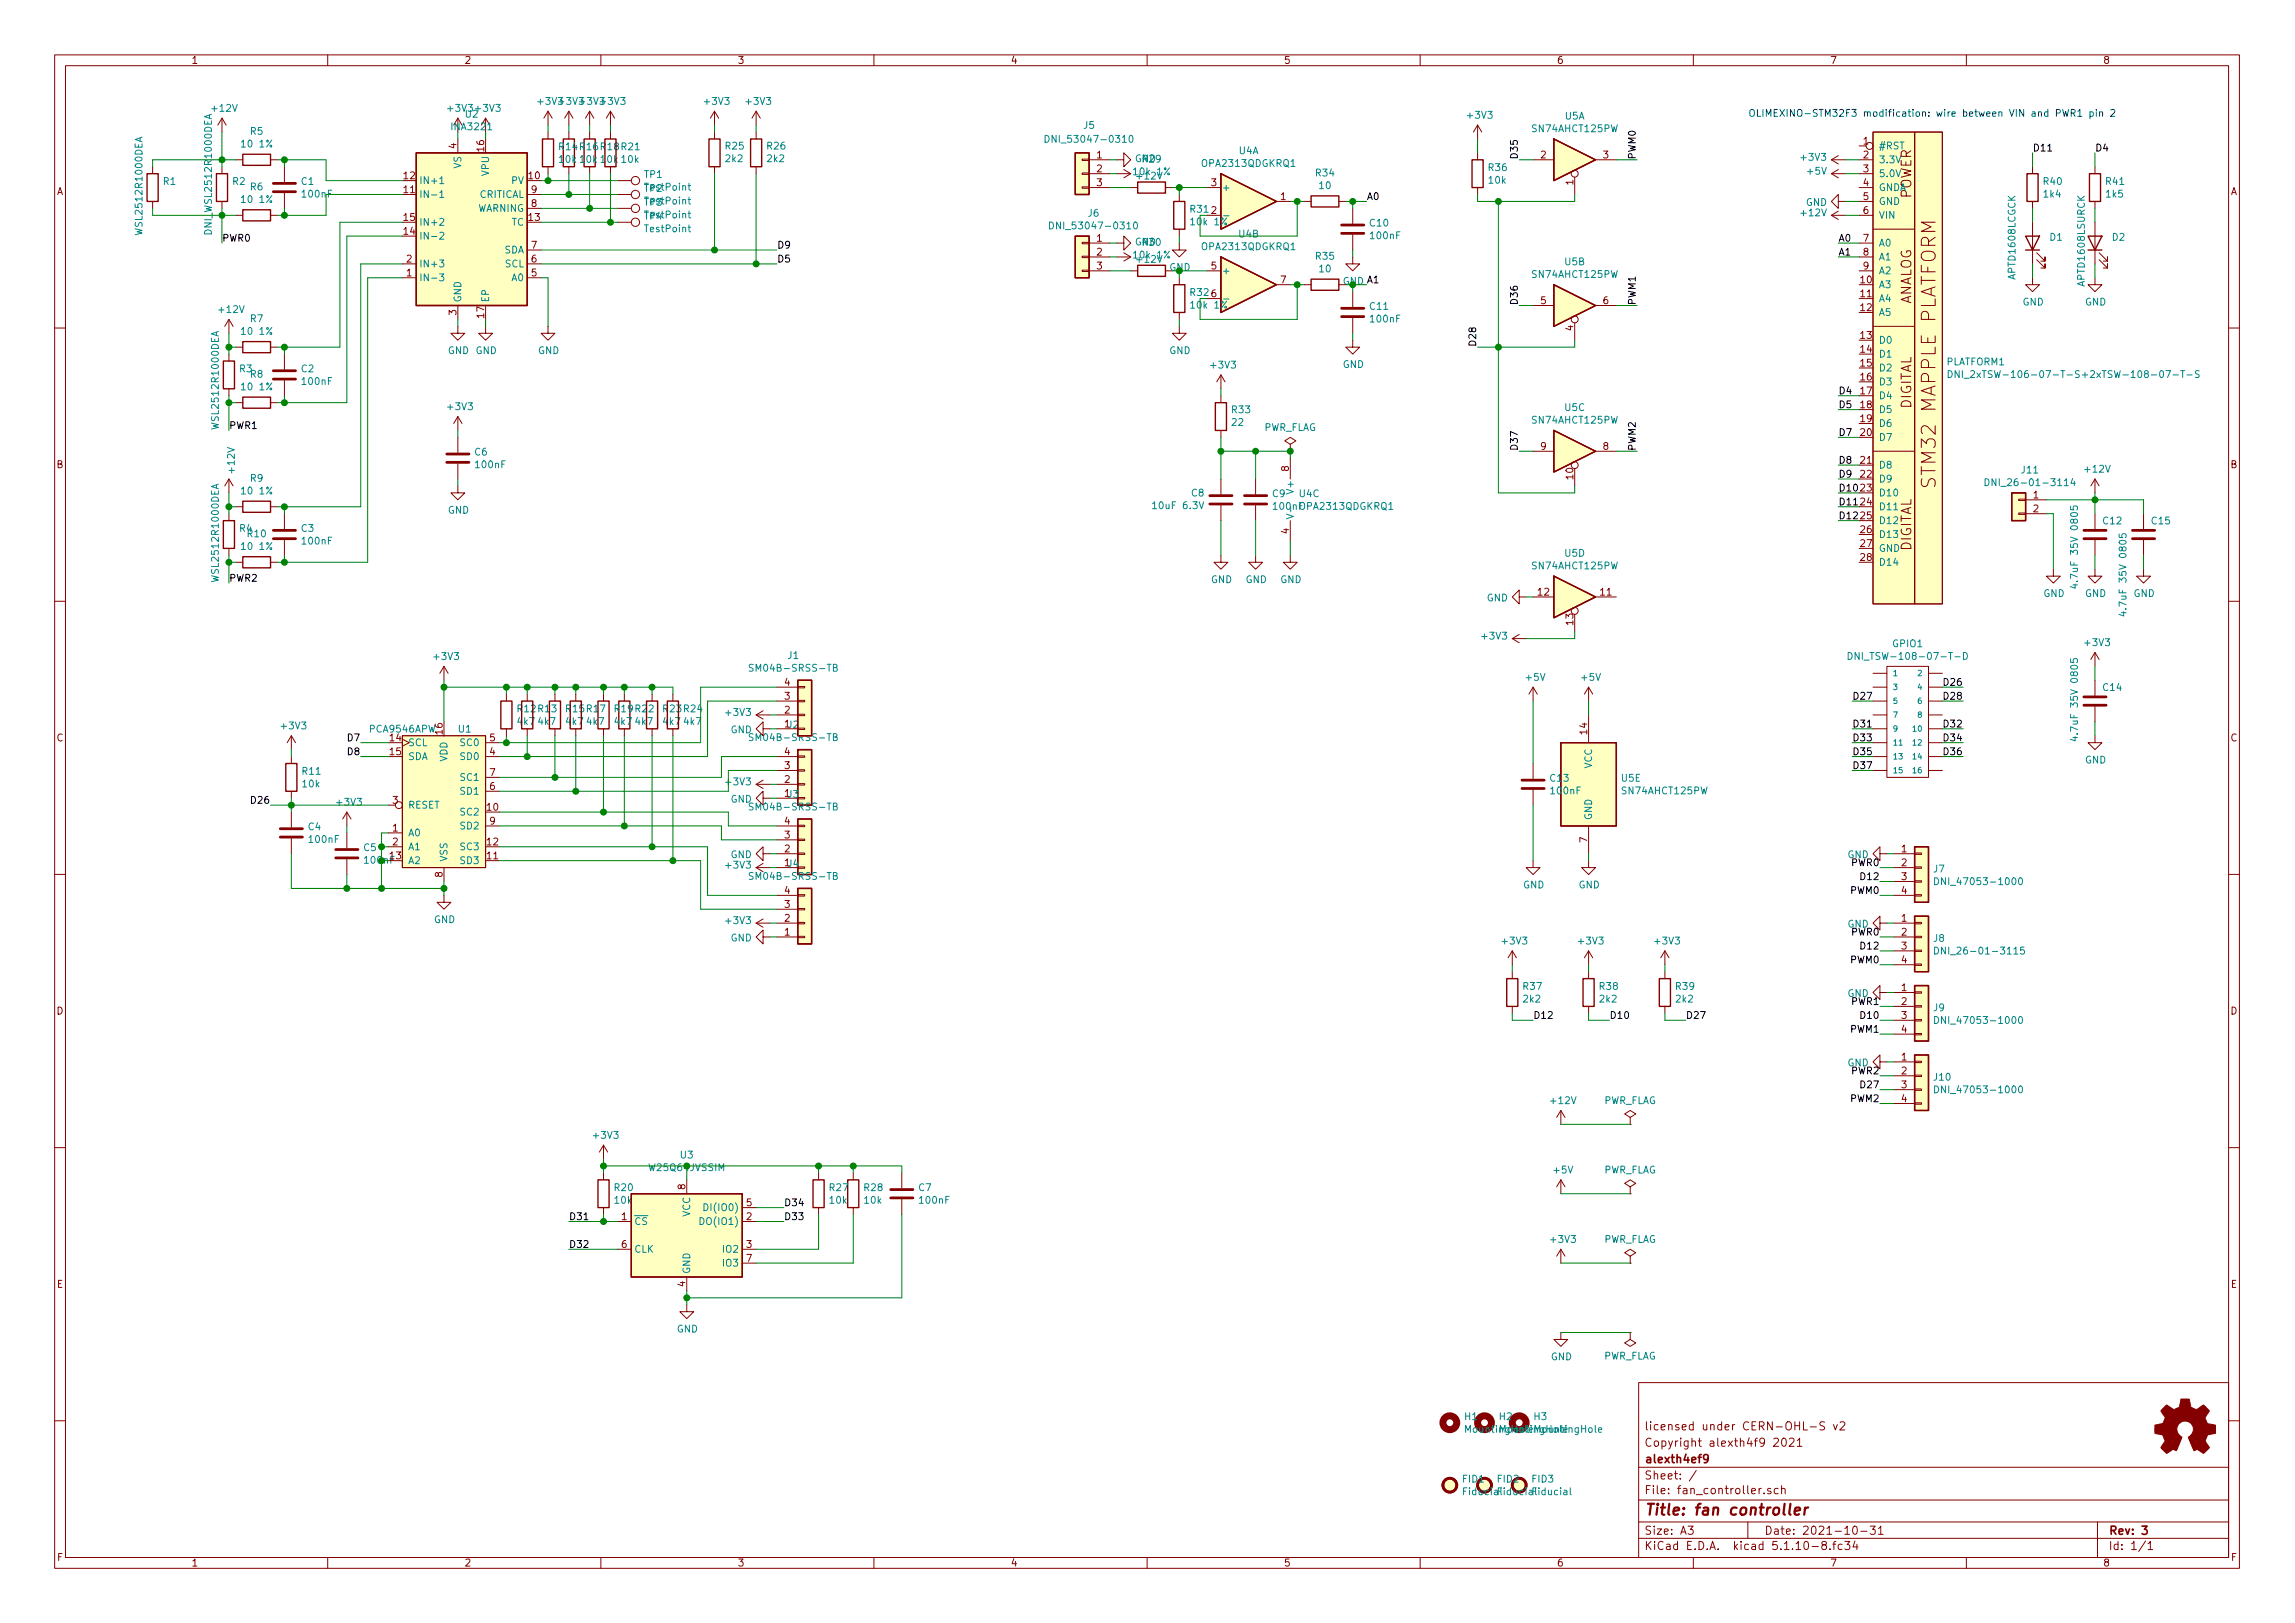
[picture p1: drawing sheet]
<svg xmlns="http://www.w3.org/2000/svg" width="420mm" height="297mm" viewBox="0 0 420 297" stroke-linecap="round" stroke-linejoin="round" font-family="sans-serif">
<defs><g id="words">
<text font-size="3.5" fill="#840000" x="354.4" y="88.7" transform="rotate(-90 354.4 88.7)">STM32 MAPPLE PLATFORM</text>
<text font-size="2.8" fill="#840000" x="301" y="277.3">Title: fan controller</text>
<g font-size="2.5" fill="#840000">
<text x="349.9" y="36.5" transform="rotate(-90 349.9 36.5)">POWER</text>
<text x="349.9" y="55.9" transform="rotate(-90 349.9 55.9)">ANALOG</text>
<text x="349.9" y="75" transform="rotate(-90 349.9 75)">DIGITAL</text>
<text x="349.9" y="101" transform="rotate(-90 349.9 101)">DIGITAL</text>
</g>
<g font-size="2.1" fill="#840000">
<text x="301" y="261.8">licensed under CERN-OHL-S v2</text>
<text x="301" y="267.8">alexth4ef9</text>
<text x="301" y="264.8">Copyright alexth4f9 2021</text>
<text x="301" y="273.5">File: fan_controller.sch</text>
<text x="301" y="270.8">Sheet: /</text>
<text x="301" y="280.9">Size: A3</text>
<text x="323" y="280.9">Date: 2021-10-31</text>
<text x="386" y="280.9">Rev: 3</text>
<text x="301" y="283.7">KiCad E.D.A. kicad 5.1.10-8.fc34</text>
<text x="386" y="283.7">Id: 1/1</text>
</g>
<g font-size="1.8" fill="#840000">
<text x="35" y="11.7">1</text>
<text x="85" y="11.7">2</text>
<text x="135" y="11.7">3</text>
<text x="185" y="11.7">4</text>
<text x="235" y="11.7">5</text>
<text x="285" y="11.7">6</text>
<text x="335" y="11.7">7</text>
<text x="385" y="11.7">8</text>
<text x="83.6" y="27.2" transform="rotate(-90 83.6 27.2)">4</text>
<text x="88.6" y="27.7" transform="rotate(-90 88.6 27.7)">16</text>
<text x="200.8" y="29">1</text>
<text x="282.1" y="29">2</text>
<text x="293.5" y="29">3</text>
<text x="341.1" y="26.5">1</text>
<text x="341.1" y="29">2</text>
<text x="10.4" y="35.7">A</text>
<text x="74" y="35.3">11</text>
<text x="74" y="32.8">12</text>
<text x="96.8" y="32.8">10</text>
<text x="97.3" y="35.3">9</text>
<text x="200.8" y="31.5">2</text>
<text x="200.8" y="34.1">3</text>
<text x="221.8" y="34.1">3</text>
<text x="288" y="33.8" transform="rotate(-90 288 33.8)">1</text>
<text x="341.1" y="31.5">3</text>
<text x="341.1" y="34.1">4</text>
<text x="408.4" y="35.7">A</text>
<text x="74" y="40.4">15</text>
<text x="96.8" y="40.4">13</text>
<text x="97.3" y="37.9">8</text>
<text x="221.8" y="39.2">2</text>
<text x="234.5" y="36.6">1</text>
<text x="341.1" y="36.6">5</text>
<text x="341.1" y="39.2">6</text>
<text x="74" y="43">14</text>
<text x="97.3" y="45.5">7</text>
<text x="200.8" y="44.2">1</text>
<text x="200.8" y="46.8">2</text>
<text x="341.1" y="44.2">7</text>
<text x="341.1" y="46.8">8</text>
<text x="74.4" y="50.6">1</text>
<text x="74.4" y="48">2</text>
<text x="97.3" y="50.6">5</text>
<text x="97.3" y="48">6</text>
<text x="200.8" y="49.3">3</text>
<text x="221.8" y="49.3">5</text>
<text x="234.5" y="51.9">7</text>
<text x="340.7" y="51.9">10</text>
<text x="341.1" y="49.3">9</text>
<text x="83.6" y="57.7" transform="rotate(-90 83.6 57.7)">3</text>
<text x="88.6" y="58.2" transform="rotate(-90 88.6 58.2)">17</text>
<text x="221.8" y="54.4">6</text>
<text x="282.1" y="55.7">5</text>
<text x="293.5" y="55.7">6</text>
<text x="340.7" y="54.4">11</text>
<text x="340.7" y="56.9">12</text>
<text x="288" y="60.5" transform="rotate(-90 288 60.5)">4</text>
<text x="340.7" y="62">13</text>
<text x="340.7" y="64.6">14</text>
<text x="340.7" y="67.1">15</text>
<text x="340.7" y="69.6">16</text>
<text x="340.7" y="72.2">17</text>
<text x="340.7" y="74.7">18</text>
<text x="340.7" y="77.3">19</text>
<text x="282.1" y="82.3">9</text>
<text x="293.5" y="82.3">8</text>
<text x="340.7" y="79.8">20</text>
<text x="10.4" y="85.7">B</text>
<text x="236" y="86.2" transform="rotate(-90 236 86.2)">8</text>
<text x="288" y="87.7" transform="rotate(-90 288 87.7)">10</text>
<text x="340.7" y="84.9">21</text>
<text x="340.7" y="87.4">22</text>
<text x="340.7" y="90">23</text>
<text x="408.4" y="85.7">B</text>
<text x="340.7" y="92.5">24</text>
<text x="340.7" y="95">25</text>
<text x="372.3" y="91.2">1</text>
<text x="372.3" y="93.8">2</text>
<text x="236" y="97.7" transform="rotate(-90 236 97.7)">4</text>
<text x="340.7" y="97.6">26</text>
<text x="340.7" y="100.1">27</text>
<text x="340.7" y="102.7">28</text>
<text x="281.6" y="109">12</text>
<text x="293" y="109">11</text>
<text x="288" y="114.3" transform="rotate(-90 288 114.3)">13</text>
<text x="143.7" y="125.5">4</text>
<text x="143.7" y="130.6">2</text>
<text x="143.7" y="128.1">3</text>
<text x="10.4" y="135.7">C</text>
<text x="71.4" y="135.7">14</text>
<text x="81" y="134.4" transform="rotate(-90 81 134.4)">16</text>
<text x="89.7" y="135.7">5</text>
<text x="143.7" y="133.1">1J2</text>
<text x="290.6" y="134.4" transform="rotate(-90 290.6 134.4)">14</text>
<text x="408.4" y="135.7">C</text>
<text x="71.4" y="138.2">15</text>
<text x="89.7" y="138.2">4</text>
<text x="89.7" y="142">7</text>
<text x="143.7" y="143.3">2</text>
<text x="143.7" y="140.8">3</text>
<text x="143.7" y="138.2">4</text>
<text x="71.9" y="147.1">3</text>
<text x="89.2" y="148.4">10</text>
<text x="89.7" y="144.6">6</text>
<text x="71.9" y="152.2">1</text>
<text x="71.9" y="154.7">2</text>
<text x="89.2" y="154.7">12</text>
<text x="89.7" y="150.9">9</text>
<text x="143.7" y="156">2</text>
<text x="143.7" y="153.5">3</text>
<text x="143.7" y="150.9">4</text>
<text x="290.6" y="154.2" transform="rotate(-90 290.6 154.2)">7</text>
<text x="348.1" y="156">1</text>
<text x="71.4" y="157.3">13</text>
<text x="81" y="160.5" transform="rotate(-90 81 160.5)">8</text>
<text x="89.2" y="157.3">11</text>
<text x="348.1" y="158.5">2</text>
<text x="348.1" y="161.1">3</text>
<text x="143.7" y="166.2">3</text>
<text x="143.7" y="163.6">4</text>
<text x="348.1" y="163.6">4</text>
<text x="143.7" y="171.2">1</text>
<text x="143.7" y="168.7">2</text>
<text x="348.1" y="168.7">1</text>
<text x="348.1" y="171.2">2</text>
<text x="348.1" y="173.8">3</text>
<text x="348.1" y="176.3">4</text>
<text x="10.4" y="185.7">D</text>
<text x="348.1" y="181.4">1</text>
<text x="348.1" y="183.9">2</text>
<text x="408.4" y="185.7">D</text>
<text x="348.1" y="186.5">3</text>
<text x="348.1" y="189">4</text>
<text x="348.1" y="194.1">1</text>
<text x="348.1" y="196.6">2</text>
<text x="348.1" y="199.2">3</text>
<text x="348.1" y="201.7">4</text>
<text x="125.5" y="217.7" transform="rotate(-90 125.5 217.7)">8</text>
<text x="136.7" y="220.8">5</text>
<text x="113.8" y="223.3">1</text>
<text x="136.7" y="223.3">2</text>
<text x="113.8" y="228.4">6</text>
<text x="136.7" y="228.4">3</text>
<text x="136.7" y="230.9">7</text>
<text x="10.4" y="235.7">E</text>
<text x="125.5" y="235.5" transform="rotate(-90 125.5 235.5)">4</text>
<text x="408.4" y="235.7">E</text>
<text x="10.5" y="285.7">F</text>
<text x="35" y="286.7">1</text>
<text x="85" y="286.7">2</text>
<text x="135" y="286.7">3</text>
<text x="185" y="286.7">4</text>
<text x="235" y="286.7">5</text>
<text x="285" y="286.7">6</text>
<text x="335" y="286.7">7</text>
<text x="385" y="286.7">8</text>
<text x="408.5" y="285.7">F</text>
</g>
<g font-size="1.8" fill="#008484">
<text x="38.9" y="20.5">+12V</text>
<text x="82.1" y="20.5">+3V3 +3V3</text>
<text x="82.9" y="23.8">INA3221</text>
<text x="85.2" y="21.5">U2</text>
<text x="98.6" y="19.2">+3V3+3V3+3V3+3V3</text>
<text x="129.1" y="19.2">+3V3</text>
<text x="136.7" y="19.2">+3V3</text>
<text x="198.4" y="23.6">J5</text>
<text x="268.8" y="21.7">+3V3</text>
<text x="286.5" y="21.9">U5A</text>
<text x="44.5" y="27">10 1%</text>
<text x="45.9" y="24.7">R5</text>
<text x="102.4" y="27.5">R14</text>
<text x="102.4" y="29.8">10k</text>
<text x="106.2" y="27.5">R16</text>
<text x="106.2" y="29.8">10k</text>
<text x="110" y="27.5">R18</text>
<text x="110.1" y="29.8">10k</text>
<text x="113.8" y="27.5">R21</text>
<text x="113.9" y="29.8">10k</text>
<text x="132.9" y="27.4">R25</text>
<text x="132.9" y="29.7">2k2</text>
<text x="140.5" y="27.4">R26</text>
<text x="140.5" y="29.7">2k2</text>
<text x="192.6" y="26.1">DNI_53047-0310</text>
<text x="209.2" y="29.8">R29</text>
<text x="226.8" y="28.2">U4A</text>
<text x="280.7" y="24.2">SN74AHCT125PW</text>
<text x="329.9" y="29.4">+3V3</text>
<text x="343.9" y="27.3">#RST</text>
<text x="343.9" y="29.9">3.3V</text>
<text x="29.9" y="33.8">R1</text>
<text x="42.6" y="33.8">R2</text>
<text x="45.9" y="34.8">R6</text>
<text x="55.2" y="33.8">C1</text>
<text x="76.7" y="33.7">IN+1</text>
<text x="84.5" y="30.8" transform="rotate(-90 84.5 30.8)">VS</text>
<text x="89.5" y="32.1" transform="rotate(-90 89.5 32.1)">VPU</text>
<text x="93.6" y="33.7">PV</text>
<text x="118" y="32.6">TP1</text>
<text x="118" y="35.1">TP2</text>
<text x="118.2" y="34.9">TestPoint</text>
<text x="207.8" y="32.1">10k 1%</text>
<text x="208.3" y="32.9">+12V</text>
<text x="220.2" y="30.5">OPA2313QDGKRQ1</text>
<text x="223.6" y="35">+</text>
<text x="240.9" y="32.3">R34</text>
<text x="241.6" y="34.6">10</text>
<text x="272.6" y="31.3">R36</text>
<text x="272.6" y="33.6">10k</text>
<text x="331" y="32">+5V</text>
<text x="343.9" y="32.4">5.0V</text>
<text x="343.9" y="35">GNDA</text>
<text x="374.2" y="33.8">R40</text>
<text x="385.6" y="33.8">R41</text>
<text x="44.5" y="37.1">10 1%</text>
<text x="55.4" y="36.2">100nF</text>
<text x="76.7" y="36.2">IN-1</text>
<text x="76.7" y="41.3">IN+2</text>
<text x="87.4" y="38.8">WARNING</text>
<text x="87.8" y="36.2">CRITICAL</text>
<text x="93.6" y="41.3">TC</text>
<text x="118" y="40.2">TP4</text>
<text x="118" y="37.7">TP3</text>
<text x="118.2" y="40">TestPoint</text>
<text x="118.2" y="37.4">TestPoint</text>
<text x="193.4" y="42">DNI_53047-0310</text>
<text x="199.2" y="39.7">J6</text>
<text x="218.3" y="41.2">10k 1%</text>
<text x="223.6" y="40">-</text>
<text x="250.9" y="41.5">C10</text>
<text x="329.9" y="39.6">+12V</text>
<text x="330.6" y="37.7">GND</text>
<text x="343.9" y="37.5">GND</text>
<text x="343.9" y="40">VIN</text>
<text x="374.2" y="36.2">1k4</text>
<text x="385.6" y="36.2">1k5</text>
<text x="26.1" y="42.5" transform="rotate(-90 26.1 42.5)">WSL2512R1000DEA</text>
<text x="38.8" y="42.4" transform="rotate(-90 38.8 42.4)">DNI_WSL2512R1000DEA</text>
<text x="76.7" y="43.9">IN-2</text>
<text x="92.3" y="46.4">SDA</text>
<text x="118.2" y="42.5">TestPoint</text>
<text x="207.8" y="47.3">10k 1%</text>
<text x="209.2" y="45">R30</text>
<text x="220.2" y="45.8">OPA2313QDGKRQ1</text>
<text x="226.8" y="43.5">U4B</text>
<text x="240.9" y="47.5">R35</text>
<text x="251" y="43.8">100nF</text>
<text x="343.9" y="45.1">A0</text>
<text x="343.9" y="47.7">A1</text>
<text x="375.3" y="44.1">D1</text>
<text x="386.7" y="44.1">D2</text>
<text x="76.7" y="51.5">IN-3</text>
<text x="76.7" y="48.9">IN+3</text>
<text x="92.5" y="48.9">SCL</text>
<text x="93.8" y="51.5">A0</text>
<text x="208.3" y="48.1">+12V</text>
<text x="223.6" y="50.2">+</text>
<text x="241.6" y="49.8">10</text>
<text x="280.7" y="50.9">SN74AHCT125PW</text>
<text x="286.5" y="48.6">U5B</text>
<text x="343.9" y="52.7">A3</text>
<text x="343.9" y="50.2">A2</text>
<text x="369" y="51" transform="rotate(-90 369 51)">APTD1608LCGCK</text>
<text x="381.7" y="52.1" transform="rotate(-90 381.7 52.1)">APTD1608LSURCK</text>
<text x="40.2" y="57.3">+12V</text>
<text x="45.9" y="59">R7</text>
<text x="84.5" y="55.4" transform="rotate(-90 84.5 55.4)">GND</text>
<text x="89.5" y="55.4" transform="rotate(-90 89.5 55.4)">EP</text>
<text x="218.3" y="56.5">10k 1%</text>
<text x="223.6" y="55.3">-</text>
<text x="250.9" y="56.7">C11</text>
<text x="251" y="59">100nF</text>
<text x="343.9" y="55.3">A4</text>
<text x="343.9" y="57.8">A5</text>
<text x="370.3" y="55.9">GND</text>
<text x="381.7" y="55.9">GND</text>
<text x="44.5" y="61.3">10 1%</text>
<text x="82" y="64.8">GND GND</text>
<text x="98.5" y="64.8">GND</text>
<text x="214.1" y="64.8">GND</text>
<text x="343.9" y="62.9">D0</text>
<text x="343.9" y="65.4">D1</text>
<text x="43.9" y="68.1">R3</text>
<text x="44.5" y="71.4">10 1%</text>
<text x="45.9" y="69.1">R8</text>
<text x="55.2" y="68.1">C2</text>
<text x="55.4" y="70.4">100nF</text>
<text x="221.8" y="67.4">+3V3</text>
<text x="245.8" y="67.3">GND</text>
<text x="343.9" y="68">D2</text>
<text x="343.9" y="70.5">D3</text>
<text x="356.3" y="66.9">PLATFORM1</text>
<text x="361.7" y="69.2">DNI_2xTSW-106-07-T-S+2xTSW-108-07-T-S</text>
<text x="82.1" y="75.1">+3V3</text>
<text x="225.6" y="75.6">R33</text>
<text x="225.6" y="77.9">22</text>
<text x="280.7" y="77.5">SN74AHCT125PW</text>
<text x="286.5" y="75.2">U5C</text>
<text x="343.9" y="73.1">D4</text>
<text x="343.9" y="75.6">D5</text>
<text x="40.1" y="78" transform="rotate(-90 40.1 78)">WSL2512R1000DEA</text>
<text x="86.9" y="83.4">C6</text>
<text x="231.3" y="78.9">PWR_FLAG</text>
<text x="343.9" y="78.1">D6</text>
<text x="343.9" y="80.7">D7</text>
<text x="43" y="86.4" transform="rotate(-90 43 86.4)">+12V</text>
<text x="45.9" y="88.2">R9</text>
<text x="87.2" y="85.7">100nF</text>
<text x="343.9" y="85.8">D8</text>
<text x="343.9" y="88.3">D9</text>
<text x="365.1" y="89">DNI_26-01-3114</text>
<text x="370.2" y="86.7">J11</text>
<text x="381.8" y="86.5">+12V</text>
<text x="44.5" y="90.5">10 1%</text>
<text x="82" y="94">GND</text>
<text x="211.5" y="93.2">10uF 6.3V</text>
<text x="218.2" y="90.9">C8</text>
<text x="233" y="91">C9</text>
<text x="233.2" y="93.3">100nFOPA2313QDGKRQ1</text>
<text x="236.9" y="90" transform="rotate(-90 236.9 90)">V+</text>
<text x="237.9" y="91">U4C</text>
<text x="343.9" y="90.8">D10</text>
<text x="343.9" y="93.4">D11</text>
<text x="343.9" y="95.9">D12</text>
<text x="385.1" y="96">C12</text>
<text x="394" y="96">C15</text>
<text x="43.9" y="97.3">R4</text>
<text x="44.5" y="100.6">10 1%</text>
<text x="45.4" y="98.3">R10</text>
<text x="55.2" y="97.3">C3</text>
<text x="55.4" y="99.7">100nF</text>
<text x="286.5" y="101.9">U5D</text>
<text x="343.9" y="98.5">D13</text>
<text x="343.9" y="101">GND</text>
<text x="40.1" y="106" transform="rotate(-90 40.1 106)">WSL2512R1000DEA</text>
<text x="221.7" y="106.7">GND</text>
<text x="228" y="106.7">GND</text>
<text x="234.4" y="106.7">GND</text>
<text x="280.7" y="104.2">SN74AHCT125PW</text>
<text x="343.9" y="103.5">D14</text>
<text x="380.4" y="106.5" transform="rotate(-90 380.4 106.5)">4.7uF 35V 0805</text>
<text x="272.2" y="110.1">GND</text>
<text x="374.1" y="109.3">GND</text>
<text x="381.7" y="109.3">GND</text>
<text x="389.3" y="111.5" transform="rotate(-90 389.3 111.5)">4.7uF 35V 0805</text>
<text x="390.6" y="109.3">GND</text>
<text x="271.4" y="117.1">+3V3</text>
<text x="346.6" y="118.5">GPIO1</text>
<text x="381.8" y="118.2">+3V3</text>
<text x="79.6" y="120.8">+3V3</text>
<text x="138.1" y="122.9">SM04B-SRSS-TB</text>
<text x="144.3" y="120.6">J1</text>
<text x="279.5" y="124.6">+5V</text>
<text x="289.6" y="124.6">+5V</text>
<text x="340.5" y="120.8">DNI_TSW-108-07-T-D</text>
<text x="94.8" y="130.4">R12</text>
<text x="98.6" y="130.4">R13</text>
<text x="103.7" y="130.4">R15</text>
<text x="107.5" y="130.4">R17</text>
<text x="112.5" y="130.4">R19</text>
<text x="116.4" y="130.4">R22</text>
<text x="121.4" y="130.4">R23</text>
<text x="125.2" y="130.4">R24</text>
<text x="133" y="131">+3V3</text>
<text x="385.1" y="126.5">C14</text>
<text x="51.6" y="133.5">+3V3</text>
<text x="67.8" y="134.1">PCA9546APW</text>
<text x="74.7" y="136.6">SCL</text>
<text x="84" y="134.1">U1</text>
<text x="84.5" y="136.6">SC0</text>
<text x="94.8" y="132.7">4k7</text>
<text x="98.6" y="132.7">4k7</text>
<text x="103.7" y="132.7">4k7</text>
<text x="107.5" y="132.7">4k7</text>
<text x="112.6" y="132.7">4k7</text>
<text x="116.4" y="132.7">4k7</text>
<text x="121.5" y="132.7">4k7</text>
<text x="125.3" y="132.7">4k7</text>
<text x="133.8" y="134.2">GND</text>
<text x="138.1" y="135.6">SM04B-SRSS-TB</text>
<text x="380.4" y="134.4" transform="rotate(-90 380.4 134.4)">4.7uF 35V 0805</text>
<text x="55.4" y="141.8">R11</text>
<text x="74.7" y="139.1">SDA</text>
<text x="81.9" y="139.4" transform="rotate(-90 81.9 139.4)">VDD</text>
<text x="84.5" y="139.1">SD0</text>
<text x="84.5" y="142.9">SC1</text>
<text x="133" y="143.7">+3V3</text>
<text x="283.9" y="143.1">C13</text>
<text x="291.5" y="140.7" transform="rotate(-90 291.5 140.7)">VCC</text>
<text x="296.9" y="143.1">U5E</text>
<text x="381.7" y="139.7">GND</text>
<text x="55.4" y="144.1">10k</text>
<text x="61.8" y="147.5">+3V3</text>
<text x="74.7" y="148">RESET</text>
<text x="84.5" y="149.3">SC2</text>
<text x="84.5" y="145.5">SD1</text>
<text x="133.8" y="146.9">GND</text>
<text x="138.1" y="148.3">SM04B-SRSS-TB</text>
<text x="143.7" y="145.8">1J3</text>
<text x="284" y="145.4">100nF</text>
<text x="297.2" y="145.4">SN74AHCT125PW</text>
<text x="56.5" y="152">C4</text>
<text x="56.7" y="154.3">100nF</text>
<text x="66.6" y="155.8">C5</text>
<text x="74.7" y="153.1">A0</text>
<text x="74.7" y="155.6">A1</text>
<text x="84.5" y="155.6">SC3</text>
<text x="84.5" y="151.8">SD2</text>
<text x="291.5" y="150.2" transform="rotate(-90 291.5 150.2)">GND</text>
<text x="74.7" y="158.2">A2</text>
<text x="81.9" y="157.8" transform="rotate(-90 81.9 157.8)">VSS</text>
<text x="84.5" y="158.2">SD3</text>
<text x="133" y="159">+3V3</text>
<text x="133.8" y="157.1">GND</text>
<text x="138.1" y="161">SM04B-SRSS-TB</text>
<text x="143.7" y="158.5">1J4</text>
<text x="338.2" y="157.1">GND</text>
<text x="354" y="159.7">J7</text>
<text x="355.5" y="162">DNI_47053-1000</text>
<text x="278.8" y="162.6">GND</text>
<text x="289" y="162.6">GND</text>
<text x="79.5" y="168.9">GND</text>
<text x="133" y="169.1">+3V3</text>
<text x="133.8" y="172.3">GND</text>
<text x="275.2" y="172.9">+3V3</text>
<text x="289.1" y="172.9">+3V3</text>
<text x="303.1" y="172.9">+3V3</text>
<text x="338.2" y="169.8">GND</text>
<text x="354" y="172.4">J8</text>
<text x="355.9" y="174.7">DNI_26-01-3115</text>
<text x="278.9" y="181.2">R37</text>
<text x="279" y="183.5">2k2</text>
<text x="292.9" y="181.2">R38</text>
<text x="292.9" y="183.5">2k2</text>
<text x="306.9" y="181.2">R39</text>
<text x="306.9" y="183.5">2k2</text>
<text x="338.2" y="182.5">GND</text>
<text x="354" y="185.1">J9</text>
<text x="355.5" y="187.4">DNI_47053-1000</text>
<text x="338.2" y="195.2">GND</text>
<text x="354.1" y="197.8">J10</text>
<text x="284" y="202.1">+12V</text>
<text x="293.5" y="202.1">PWR_FLAG</text>
<text x="355.5" y="200.1">DNI_47053-1000</text>
<text x="108.8" y="208.4">+3V3</text>
<text x="124.6" y="212">U3</text>
<text x="284.5" y="214.8">+5V</text>
<text x="293.5" y="214.8">PWR_FLAG</text>
<text x="112.5" y="218">R20</text>
<text x="112.6" y="220.3">10k</text>
<text x="129.6" y="221.7">DI(IO0)</text>
<text x="151.9" y="218">R27</text>
<text x="152" y="220.3">10k</text>
<text x="158.3" y="218">R28</text>
<text x="158.3" y="220.3">10k</text>
<text x="168.2" y="218">C7</text>
<text x="168.5" y="220.3">100nF</text>
<text x="116.1" y="224.2">CS</text>
<text x="126.4" y="222.7" transform="rotate(-90 126.4 222.7)">VCC</text>
<text x="128.7" y="224.2">DO(IO1)</text>
<text x="284" y="227.5">+3V3</text>
<text x="293.5" y="227.5">PWR_FLAG</text>
<text x="116.1" y="229.3">CLK</text>
<text x="126.4" y="233.2" transform="rotate(-90 126.4 233.2)">GND</text>
<text x="132.5" y="229.3">IO2</text>
<text x="132.5" y="231.8">IO3</text>
<text x="123.9" y="243.9">GND</text>
<text x="283.9" y="249">GND</text>
<text x="293.5" y="248.8">PWR_FLAG</text>
<text x="268.2" y="259.9">H1</text>
<text x="268.5" y="262.2">MountingHole</text>
<text x="274.5" y="259.9">H2</text>
<text x="274.9" y="262.2">MountingHole</text>
<text x="280.9" y="259.9">H3</text>
<text x="281.2" y="262.2">MountingHole</text>
<text x="267.8" y="271.3">FID1</text>
<text x="268.1" y="273.6">FiducialFiducialFiducial</text>
<text x="274.2" y="271.3">FID2</text>
<text x="280.5" y="271.3">FID3</text>
</g>
<text font-size="1.8" fill="#0000c2" x="320" y="21.4">OLIMEXINO-STM32F3 modification: wire between VIN and PWR1 pin 2</text>
<g font-size="1.8">
<text x="277.9" y="29.2" transform="rotate(-90 277.9 29.2)">D35</text>
<text x="299.5" y="29.2" transform="rotate(-90 299.5 29.2)">PWM0</text>
<text x="372.1" y="27.7">D11</text>
<text x="383.5" y="27.7">D4</text>
<text x="250.2" y="36.6">A0</text>
<text x="40.6" y="44.2">PWR0</text>
<text x="142.2" y="45.5">D9</text>
<text x="336.5" y="44.2">A0</text>
<text x="336.5" y="46.8">A1</text>
<text x="142.2" y="48">D5</text>
<text x="277.9" y="55.9" transform="rotate(-90 277.9 55.9)">D36</text>
<text x="299.5" y="55.9" transform="rotate(-90 299.5 55.9)">PWM1</text>
<text x="270.3" y="63.5" transform="rotate(-90 270.3 63.5)">D28</text>
<text x="336.5" y="74.7">D5</text>
<text x="336.5" y="72.2">D4</text>
<text x="41.9" y="78.5">PWR1</text>
<text x="277.9" y="82.6" transform="rotate(-90 277.9 82.6)">D37</text>
<text x="299.5" y="82.6" transform="rotate(-90 299.5 82.6)">PWM2</text>
<text x="336.5" y="79.8">D7</text>
<text x="336.5" y="87.4">D9</text>
<text x="336.5" y="90">D10</text>
<text x="336.5" y="84.9">D8</text>
<text x="336.5" y="95">D12</text>
<text x="336.5" y="92.5">D11</text>
<text x="41.9" y="106.5">PWR2</text>
<text x="356.2" y="125.5">D26</text>
<text x="339.1" y="128.1">D27</text>
<text x="356.2" y="128.1">D28</text>
<text x="63.8" y="135.7">D7</text>
<text x="339.1" y="135.7">D33</text>
<text x="339.1" y="133.1">D31</text>
<text x="356.2" y="135.7">D34</text>
<text x="356.2" y="133.1">D32</text>
<text x="63.8" y="138.2">D8</text>
<text x="339.1" y="138.2">D35</text>
<text x="339.1" y="140.8">D37</text>
<text x="356.2" y="138.2">D36</text>
<text x="46.3" y="147.1">D26</text>
<text x="339.1" y="158.5">PWR0</text>
<text x="340.9" y="161.1">D12</text>
<text x="338.9" y="163.6">PWM0</text>
<text x="339.1" y="171.2">PWR0</text>
<text x="340.9" y="173.8">D12</text>
<text x="338.9" y="176.3">PWM0</text>
<text x="339.1" y="183.9">PWR1</text>
<text x="280.7" y="186.5">D12</text>
<text x="294.6" y="186.5">D10</text>
<text x="308.6" y="186.5">D27</text>
<text x="338.9" y="189">PWM1</text>
<text x="340.9" y="186.5">D10</text>
<text x="339.1" y="196.6">PWR2</text>
<text x="338.9" y="201.7">PWM2</text>
<text x="340.9" y="199.2">D27</text>
<text x="143.5" y="220.8">D34</text>
<text x="104.1" y="223.3">D31</text>
<text x="143.5" y="223.3">D33</text>
<text x="104.1" y="228.4">D32</text>
</g>
<g font-size="1.8" fill="#008400">
<text x="218" y="38.9">R31</text>
<text x="214.1" y="49.6">GND</text>
<text x="245.8" y="52.1">GND A1</text>
<text x="218" y="54.2">R32</text>
<text x="66.9" y="158.1">100nF</text>
<text x="119" y="214.3">W25Q64JVSSIM</text>
</g>
<g font-size="1.4" fill="#008484">
<text x="346.5" y="123.7">1</text>
<text x="351.3" y="123.7">2</text>
<text x="346.5" y="126.3">3</text>
<text x="346.5" y="128.8">5</text>
<text x="346.5" y="131.4">7</text>
<text x="351.3" y="126.3">4</text>
<text x="351.3" y="128.8">6</text>
<text x="351.3" y="131.4">8</text>
<text x="346.5" y="136.4">11</text>
<text x="346.5" y="133.9">9</text>
<text x="350.5" y="133.9">10</text>
<text x="350.5" y="136.4">12</text>
<text x="346.5" y="139">13</text>
<text x="346.5" y="141.5">15</text>
<text x="350.5" y="139">14</text>
<text x="350.5" y="141.5">16</text>
</g>
</g></defs>
<g fill="none" stroke="#840000" stroke-width=".18">
<path d="M10 10h400v277h-400zM12 12h396v273.1h-396zM60 10v2M110 10v2M160 10v2M210 10v2M260 10v2M310 10v2M360 10v2M27.9 30.5v1.3M27.9 36.9v1.2M40.6 21.6l-.7 1.3"/>
<path d="M40.6 21.6v2.6M40.6 30.5v1.3M40.6 36.9v1.2M40.6 21.6l.8 1.3M43.2 39.4h1.2M43.2 29.2h1.2M49.5 39.4h1.3M49.5 29.2h1.3M52.1 30.5v2.8M52.1 35.3v2.8M83.8 21.6l-.7 1.3M83.8 21.6v2.6"/>
<path d="M83.8 25.4v2.6M83.8 21.6l.8 1.3M88.9 21.6l-.8 1.3M88.9 21.6v2.6M88.9 21.6l.8 1.3M96.5 38.1h2.6M96.5 35.6h2.6M100.3 20.4l-.7 1.2M100.3 20.4v2.5M100.3 24.2v1.2M100.3 30.5v1.3M100.3 20.4l.8 1.2"/>
<path d="M104.1 20.4l-.7 1.2M104.1 20.4v2.5M104.1 24.2v1.2M104.1 30.5v1.3M104.1 20.4l.8 1.2M107.9 20.4l-.7 1.2M107.9 20.4v2.5M107.9 24.2v1.2M107.9 30.5v1.3M107.9 20.4l.8 1.2M111.8 20.4l-.8 1.2M111.8 20.4v2.5"/>
<path d="M111.8 24.2v1.2M111.8 30.5v1.3M111.8 20.4l.7 1.2M113 33.1h2.6M113 38.1h2.6M113 35.6h2.6M130.8 20.4l-.8 1.2M130.8 20.4v2.5M130.8 24.2v1.2M130.8 30.5v1.3M130.8 20.4l.8 1.2M138.4 20.4l-.7 1.2"/>
<path d="M138.4 20.4v2.5M138.4 24.2v1.2M138.4 30.5v1.3M138.4 20.4l.8 1.2M198.1 34.2h1.3v.3h-1.3zM198.1 29.1h1.3v.3h-1.3zM198.1 31.7h1.3v.2h-1.3zM199.4 29.2h3.8M199.4 34.3h3.8M199.4 31.8h3.8M204.5 29.2h1.2v-1.2l1.3 1.2-1.3 1.3v-1.3M204.5 31.8h2.5"/>
<path d="M205.7 31l1.3 .8M207 34.3h1.3M207 31.8l-1.3 .7M213.4 34.3h1.2M215.9 35.6v1.3M221 34.3h2.5M233.7 36.9h2.5M238.8 36.9h1.2M245.1 36.9h1.3M247.6 38.1v2.8M270.5 22.9v2.5M270.5 28v1.2"/>
<path d="M270.5 34.3v1.3M270.5 22.9l-.8 1.3M270.5 22.9l.8 1.3M280.7 29.2h3.8M288.3 32.4v3.2M292.1 29.2h3.8M335.3 39.4h2.5M335.3 29.2h2.5M335.3 29.2l1.2 .8M335.3 39.4l1.2 .8M335.3 31.8l1.2 .7M335.3 31.8h2.5"/>
<path d="M336.5 36.9v-1.3l-1.2 1.3 1.2 1.2v-1.2h1.3M336.5 28.5l-1.2 .7M336.5 38.6l-1.2 .8M336.5 31l-1.2 .8M340.4 39.4h2.5M340.4 29.2h2.5M340.4 36.9h2.5M340.4 34.3h2.5M340.4 31.8h2.5M340.4 26.7h1.2M342.9 24.2h7.6v86.3h-7.6zM350.5 24.2h5.1v86.3h-5.1z"/>
<path d="M372.1 30.5v1.3M372.1 36.9v1.2M383.5 30.5v1.3M383.5 36.9v1.2M41.9 58.5v2.5M41.9 58.5l-.8 1.2M41.9 58.5l.8 1.2M73.7 50.8h2.5M73.7 48.3h2.5M83.8 59.7v1.3h1.3l-1.3 1.3-1.3-1.3h1.3M83.8 55.9v2.6M88.9 59.7v1.3h1.3l-1.3 1.3-1.3-1.3h1.3"/>
<path d="M96.5 50.8h2.6M96.5 48.3h2.6M96.5 45.8h2.6M100.3 59.7v1.3h1.3l-1.3 1.3-1.2-1.3h1.2M113 40.7h2.6M198.1 49.4h1.3v.3h-1.3zM198.1 44.4h1.3v.2h-1.3zM198.1 46.9h1.3v.3h-1.3zM199.4 49.6h3.8M199.4 44.5h3.8M199.4 47h3.8M204.5 44.5h1.2v-1.3l1.3 1.3-1.3 1.3v-1.3"/>
<path d="M204.5 47h2.5M205.7 46.3l1.3 .7M207 49.6h1.3M207 47l-1.3 .8M213.4 49.6h1.2M215.9 44.5v1.3h1.3l-1.3 1.2-1.3-1.2h1.3M215.9 59.7v1.3h1.3l-1.3 1.3-1.3-1.3h1.3M215.9 41.9v1.3M215.9 50.8v1.3M215.9 57.2v1.3M221 49.6h2.5M233.7 52.1h2.5"/>
<path d="M238.8 52.1h1.2M245.1 52.1h1.3M247.6 47v1.3h1.3l-1.3 1.3-1.2-1.3h1.2M247.6 43v2.8M247.6 53.4v2.8M247.6 58.2v2.8M280.7 55.9h3.8M288.3 59.1v3.2M292.1 55.9h3.8M340.4 49.6h2.5M340.4 44.5h2.5M340.4 47h2.5"/>
<path d="M342.9 41.9h7.6M342.9 59.7h7.6M354.3 40.7h-2.6l1.8 .8-1.8 .9h2.6M372.1 50.8v1.3h1.3l-1.3 1.3-1.3-1.3h1.3M372.1 40.7v7.6M372.9 47.5l1.5 1.6v-.8v.8h-.8M372.9 46.3l1.5 1.5v-.8v.8h-.8M383.5 50.8v1.3h1.3l-1.3 1.3-1.2-1.3h1.2M383.5 40.7v7.6M384.3 47.5l1.5 1.6v-.8v.8h-.7M384.3 46.3l1.5 1.5v-.8v.8h-.7M10 60h2"/>
<path d="M41.9 64.8v1.3M41.9 71.2v1.2M43.2 73.7h1.2M43.2 63.5h1.2M49.5 73.7h1.3M49.5 63.5h1.3M52.1 64.8v2.8M52.1 69.6v2.8M83.8 76.2v2.6M83.8 76.2l-.7 1.3M83.8 76.2l.8 1.3M223.5 68.6l-.7 1.3"/>
<path d="M223.5 68.6v2.6M223.5 72.4v1.3M223.5 78.8v1.2M223.5 68.6l.8 1.3M247.6 62.3v1.2h1.3l-1.3 1.3-1.2-1.3h1.2M408 60h2M41.9 87.7v2.5M41.9 94v1.3M41.9 87.7l-.8 1.2M41.9 87.7l.8 1.2M43.2 92.7h1.2M49.5 92.7h1.3"/>
<path d="M52.1 94v2.8M52.1 98.8v2.8M83.8 88.9v1.3h1.3l-1.3 1.3-1.3-1.3h1.3M83.8 80v2.8M83.8 84.9v2.8M223.5 87.7v2.8M223.5 92.5v2.8M229.9 87.7v2.8M229.9 92.5v2.8M236.2 81.3l1-.6-1-.7-1 .7 1 .6v1.3M236.2 82.6h.1M236.2 83.9v3.8"/>
<path d="M236.2 95.3v3.8M280.7 82.6h3.8M288.3 85.8v3.1M292.1 82.6h3.8M342.9 82.6h7.6M369.6 93.9h1.2v.2h-1.2zM369.6 91.3h1.2v.3h-1.2zM370.8 91.5h3.8M370.8 94h3.8M383.5 87.7v2.5M383.5 94v2.8M383.5 98.8v2.8"/>
<path d="M383.5 87.7l-.7 1.2M383.5 87.7l.8 1.2M392.4 94v2.8M392.4 98.8v2.8M10 110h2M41.9 100.4v1.2M43.2 102.9h1.2M49.5 102.9h1.3M223.5 101.6v1.3h1.3l-1.3 1.3-1.3-1.3h1.3M229.9 101.6v1.3h1.2l-1.2 1.3-1.3-1.3h1.3M236.2 101.6v1.3h1.3l-1.3 1.3-1.3-1.3h1.3M276.9 116.9l1.2 .7"/>
<path d="M276.9 116.9h2.5M278.1 109.3v-1.3l-1.2 1.3 1.2 1.2v-1.2h1.3M278.1 116.1l-1.2 .8M280.7 109.3h3.8M288.3 112.4v3.2M292.1 109.3h3.8M375.9 104.2v1.2h1.3l-1.3 1.3-1.3-1.3h1.3M383.5 104.2v1.2h1.3l-1.3 1.3-1.2-1.3h1.2M383.5 119.4v2.6M383.5 119.4l-.7 1.3M383.5 119.4l.8 1.3M392.4 104.2v1.2h1.3l-1.3 1.3-1.2-1.3h1.2"/>
<path d="M408 110h2M53.3 134.7l-.7 1.2M53.3 134.7v2.5M53.3 138.5v1.2M53.3 134.7l.8 1.2M73.7 134.7h15.2v24.1h-15.2zM73.7 135.3l1.2 .6-1.2 .7M81.3 122v2.5M81.3 122l-.8 1.2M81.3 122l.7 1.2M88.9 138.5h2.5M88.9 135.9h2.5"/>
<path d="M92.7 127v1.3M92.7 133.4v1.3M96.5 127v1.3M96.5 133.4v1.3M101.6 127v1.3M101.6 133.4v1.3M105.4 127v1.3M105.4 133.4v1.3M110.5 127v1.3M110.5 133.4v1.3M114.3 127v1.3M114.3 133.4v1.3"/>
<path d="M119.4 127v1.3M119.4 133.4v1.3M123.2 127v1.3M123.2 133.4v1.3M138.4 130.8l1.3 .8M138.4 130.8h2.6M139.7 133.4v-1.3l-1.3 1.3 1.3 1.3v-1.3h1.3M139.7 130.1l-1.3 .7M142.2 138.5h3.8M142.2 130.8h3.8M142.2 133.4h3.8M142.2 128.3h3.8"/>
<path d="M142.2 125.8h3.8M146 138.3h1.3v.3h-1.3zM146 125.6h1.3v.3h-1.3zM146 128.2h1.3v.2h-1.3zM146 133.3h1.3v.2h-1.3zM146 130.7h1.3v.3h-1.3zM280.7 125.8v2.5M280.7 139.7v2.8M280.7 125.8l-.8 1.2M280.7 125.8l.7 1.2M290.8 125.8v2.5M290.8 130.8v5.1"/>
<path d="M290.8 125.8l-.7 1.2M290.8 125.8l.8 1.2M342.9 138.5h2.5M342.9 130.8h2.5M342.9 133.4h2.5M342.9 128.3h2.5M342.9 125.8h2.5M342.9 135.9h2.5M342.9 123.2h2.5M345.4 122h7.7v20.3h-7.7zM353.1 138.5h2.5M353.1 130.8h2.5"/>
<path d="M353.1 133.4h2.5M353.1 128.3h2.5M353.1 125.8h2.5M353.1 135.9h2.5M353.1 123.2h2.5M383.5 134.7v1.2h1.3l-1.3 1.3-1.2-1.3h1.2M383.5 124.5v2.8M383.5 129.3v2.8M53.3 144.8v1.3M53.3 148.6v2.8M53.3 153.5v2.7M63.5 148.6v2.6"/>
<path d="M63.5 152.4v2.8M63.5 157.3v2.8M63.5 148.6l-.8 1.3M63.5 148.6l.8 1.3M71.1 152.4h2.6M71.1 155h2.6M71.1 147.4h1.3M81.3 158.8v2.5M88.9 151.2h2.5M88.9 144.8h2.5M88.9 142.3h2.5M138.4 143.5l1.3 .8"/>
<path d="M138.4 143.5h2.6M138.4 158.8l1.3 .7M138.4 158.8h2.6M139.7 146.1v-1.3l-1.3 1.3 1.3 1.3v-1.3h1.3M139.7 156.2v-1.2l-1.3 1.2 1.3 1.3v-1.3h1.3M139.7 142.8l-1.3 .7M139.7 158l-1.3 .8M142.2 143.5h3.8M142.2 158.8h3.8M142.2 146.1h3.8M142.2 141h3.8M142.2 156.2h3.8"/>
<path d="M142.2 153.7h3.8M142.2 151.2h3.8M146 140.9h1.3v.2h-1.3zM146 146h1.3v.2h-1.3zM146 143.4h1.3v.3h-1.3zM146 151h1.3v.3h-1.3zM146 153.6h1.3v.2h-1.3zM146 158.7h1.3v.2h-1.3zM146 156.1h1.3v.3h-1.3zM280.7 157.5v1.3h1.2l-1.2 1.3-1.3-1.3h1.3M280.7 144.6v2.8M290.8 157.5v1.3h1.3l-1.3 1.3-1.2-1.3h1.2"/>
<path d="M290.8 151.2v5M342.9 141h2.5M344.2 156.2v-1.2l-1.3 1.2 1.3 1.3v-1.3h1.2M346.7 158.8h3.8M346.7 156.2h3.8M350.5 156.1h1.3v.3h-1.3zM350.5 158.7h1.3v.2h-1.3zM353.1 141h2.5M10 160h2M81.3 163.9v1.2h1.2l-1.2 1.3-1.3-1.3h1.3M138.4 168.9l1.3 .8M138.4 168.9h2.6"/>
<path d="M139.7 171.5v-1.3l-1.3 1.3 1.3 1.3v-1.3h1.3M139.7 168.2l-1.3 .7M142.2 168.9h3.8M142.2 171.5h3.8M142.2 163.9h3.8M142.2 166.4h3.8M146 163.7h1.3v.3h-1.3zM146 166.3h1.3v.2h-1.3zM146 171.4h1.3v.2h-1.3zM146 168.8h1.3v.3h-1.3zM276.9 174v2.6M276.9 177.8v1.3"/>
<path d="M276.9 174l-.8 1.3M276.9 174l.7 1.3M290.8 174v2.6M290.8 177.8v1.3M290.8 174l-.7 1.3M290.8 174l.8 1.3M304.8 174l-.8 1.3M304.8 174v2.6M304.8 177.8v1.3M304.8 174l.8 1.3M344.2 168.9v-1.2l-1.3 1.2 1.3 1.3v-1.3h1.2M346.7 168.9h3.8"/>
<path d="M346.7 171.5h3.8M346.7 174h3.8M346.7 176.6h3.8M346.7 161.3h3.8M346.7 163.9h3.8M350.5 176.4h1.3v.3h-1.3zM350.5 173.9h1.3v.3h-1.3zM350.5 168.8h1.3v.3h-1.3zM350.5 171.4h1.3v.2h-1.3zM350.5 163.7h1.3v.3h-1.3zM350.5 161.2h1.3v.3h-1.3zM408 160h2"/>
<path d="M276.9 184.2v1.3M290.8 184.2v1.3M304.8 184.2v1.3M344.2 181.6v-1.2l-1.3 1.2 1.3 1.3v-1.3h1.2M344.2 194.3v-1.2l-1.3 1.2 1.3 1.3v-1.3h1.2M346.7 181.6h3.8M346.7 184.2h3.8M346.7 186.7h3.8M346.7 189.3h3.8M346.7 194.3h3.8M346.7 196.9h3.8M346.7 199.4h3.8"/>
<path d="M350.5 189.1h1.3v.3h-1.3zM350.5 186.6h1.3v.3h-1.3zM350.5 181.5h1.3v.3h-1.3zM350.5 184.1h1.3v.2h-1.3zM350.5 199.3h1.3v.3h-1.3zM350.5 194.2h1.3v.3h-1.3zM350.5 196.8h1.3v.2h-1.3zM10 210h2M110.5 209.6v2.5M110.5 214.7v1.2M110.5 209.6l-.8 1.3M110.5 209.6l.8 1.3"/>
<path d="M125.7 215.9v2.6M149.9 214.7v1.2M156.2 214.7v1.2M165.1 214.7v2.8M165.1 219.5v2.8M285.7 215.9l-.7 1.3M285.7 203.2v2.6M285.7 215.9v2.6M285.7 215.9l.8 1.3M285.7 203.2l-.7 1.3M285.7 203.2l.8 1.3M298.4 204.5l1.1-.6-1.1-.7-1 .7 1 .6v1.3"/>
<path d="M298.4 205.8h.1M298.4 217.2l1.1-.6-1.1-.7-1 .7 1 .6v1.3M298.4 218.5h.1M346.7 202h3.8M350.5 201.8h1.3v.3h-1.3zM408 210h2M110.5 221v1.3M113 223.6h2.6M113 228.6h2.6M125.7 238.8v1.3h1.3l-1.3 1.2-1.2-1.2h1.2M125.7 233.7v2.6M135.9 223.6h2.5"/>
<path d="M135.9 228.6h2.5M135.9 221h2.5M135.9 231.2h2.5M149.9 221v1.3M156.2 221v1.3M285.7 228.6v2.6M285.7 228.6l-.7 1.3M285.7 228.6l.8 1.3M298.4 229.9l1.1-.6-1.1-.7-1 .7 1 .6v1.3M298.4 231.2h.1M285.7 243.9v1.2h1.3l-1.3 1.3-1.2-1.3h1.2M298.4 243.9v1.2l1.1 .7-1.1 .6-1-.6 1-.7"/>
<path d="M298.4 243.9h.1M300 253h108v32.1h-108zM10 260h2M300 278.5h108M300 274.5h108M300 268.5h108M309 279.3h1l-.5 .6 .4 .1v.7l-.2 .1-.7-.1M310.5 269.1l-1.2 2M320 278.5v3M323 273.3v.1M324.2 272.5a.37 .37 0 0 0-.6 .1l.1 .2 .5 .2 .1 .1-.3 .3-.4-.1M324.7 263.4l.6-.2 .3 .4-.9 1.1h.9"/>
<path d="M325.5 272.5l-.4-.1-.3 .3 .1 .6 .2 .1 .4-.1M326.2 272.5a.37 .37 0 0 1 .6 .1v.8M326.2 271.9v1.5M326.3 263.4l.2-.2a.86 .86 0 0 1 .2 1.5 .79 .79 0 0 1-.4-1.3zM327.6 263.4l.2-.2h.4l.2 .2v.2v.2l-.9 .9h.9M329 263.6l.5-.4v1.5M329 264.7h.9M331.4 261.1h1.1M334 260.3l-.5-.1-.3 .3 .1 .3 .7 .3v.5l-.3 .1-.5-.1M335.7 260.7l.3 1 .4-1M336.9 260.4l.2-.2h.3l.3 .2v.2l-.9 1.1h.9M339.3 279.5l.2-.2a.86 .86 0 0 1 .2 1.5 .79 .79 0 0 1-.4-1.3z"/>
<path d="M342.4 279.3h.9l-.5 .6 .5 .1v.7l-.3 .1-.6-.1M343.9 279.7l.4-.4v1.5M384 278.5v6.6M408 260h2M60 285.1v1.9M110 285.1v1.9M160 285.1v1.9M210 285.1v1.9M260 285.1v1.9M300 281.5h108M310 285.1v1.9M331.7 283h1.2"/>
<path d="M333.8 282.7l-.3-.2 .3-.4 .5 .2 .1 .2-.2 .2a.52 .52 0 0 0-.6 .2 .52 .52 0 0 0 .1 .6l.4 .1 .2-.1 .1-.5-.3-.3M335 283.5v.1M335.5 282.6h.6M336.1 282.1l-.4 .2v1.3M337.2 282.7l-.4-.1-.3 .3 .2 .6h.5M337.7 282.1h1l-.5 .6 .4 .1v.7l-.2 .1-.7-.1M339.6 282l-.4 1.1h1M340 282.6v1M340.7 280.2h1.1M343.9 280.8h.9M360 285.1v1.9M392.8 282l-1.3 2"/>
<path d="M393.2 282.5l.5-.4v1.5M393.2 283.6h.9"/>
<circle cx="116.3" cy="35.6" r=".76"/>
<circle cx="116.3" cy="38.1" r=".76"/>
<circle cx="116.3" cy="33.1" r=".76"/>
<circle cx="288.3" cy="31.8" r=".63"/>
<circle cx="342.3" cy="26.7" r=".63"/>
<circle cx="116.3" cy="40.7" r=".76"/>
<circle cx="288.3" cy="58.5" r=".63"/>
<circle cx="288.3" cy="85.1" r=".63"/>
<circle cx="288.3" cy="111.8" r=".63"/>
<circle cx="73" cy="147.4" r=".63"/>
</g>
<path d="M312.7 266.8l-.3 .3h-.4l-.1-.3 .1-.5 .4-.1 .3 .2a1.27 1.27 0 0 1-.3 1.2l-.4 .1M392.2 279.3h.9l-.5 .6 .4 .1v.7l-.2 .1-.6-.1" fill="none" stroke="#840000" stroke-width=".3"/>
<path d="M327.8 275.2l-.2 1.7 .2 .3M328.6 276.6l.9-.2v-.4h-.8l-.2 .9 .3 .3 .6-.1M330.5 275.9l-.2 1.3M331 275.9a.54 .54 0 0 0-.6 .4" fill="none" stroke="#840000" stroke-width=".41"/>
<g fill="none" stroke="#008484" stroke-width=".18">
<path d="M25.7 25.2v.6M26 25.1l-1.3 .4 1.3 .4M38.4 21v.7M38.7 20.9l-1.3 .4 1.3 .5M80.5 35.2l.4-.3v1.3M80.5 32.7l.4-.4v1.3M80.5 36.2h.8M80.5 33.6h.8M89.3 23.8h.7M126 34h.4M126 39.1h.4M126 36.5h.4"/>
<path d="M126.1 33.5v1.1l.3 .2M126.1 38.6v1.1l.3 .2M126.1 36.1v1.1l.3 .1M191.3 24.8a.64 .64 0 0 1 .8 .6 .64 .64 0 0 1-.8 .6zM206.8 24.9l.2-.1a.69 .69 0 0 1 .4 .6 .69 .69 0 0 1-.4 .6l-.2-.2-.1-.2zM208.7 28.4a.59 .59 0 0 0-.7 .6 .59 .59 0 0 0 .7 .6l.1-.5h-.2M224 39.5h1M236.3 30.5h.8M80.5 50.1h.8l-.5 .5 .4 .1 .1 .5-.3 .2-.5-.1M80.5 47.6h.8l-.5 .5 .4 .1 .1 .4-.3 .3-.5-.2M80.5 42.6l.5-.1 .3 .4-.8 .9h.8M80.5 40.1l.5-.1 .3 .3-.8 .9h.8"/>
<path d="M126 41.6h.4M126.1 41.2v1.1l.3 .1M192.2 40.6a.64 .64 0 0 1 .7 .7 .64 .64 0 0 1-.7 .6zM207.7 40.7l.1-.1a.69 .69 0 0 1 .4 .7 .69 .69 0 0 1-.4 .6 .83 .83 0 0 1-.1-1.2zM208.7 43.6a.59 .59 0 0 0-.7 .6 .59 .59 0 0 0 .7 .6l.1-.5h-.2M224 54.7h1M236.3 45.7h.8M39.6 60.8v.6M40 60.7l-1.3 .4 1.3 .4M356.7 67.8a.64 .64 0 0 1 .7 .7 .64 .64 0 0 1-.7 .6zM358.7 67.8v1.3l-.8-1.3v1.3M359.3 67.8v1.3"/>
<path d="M359.6 69.2h.9M360.8 68l.5-.2 .2 .4-.1 .2-.7 .7h.8M397.8 68.6h1M399.2 67.8h.8M399.6 67.8v1.3M400.4 68.6h.9M402.6 67.9l-.5-.1-.1 .2v.3l.5 .3 .1 .3-.2 .2-.5-.1M39.6 88.7v.6M40 88.6l-1.3 .4 1.3 .4M211 92.2l.4-.4v1.3M211 93.1h.7M219.5 91.8l.5 1.3 .4-1.3"/>
<path d="M235.5 94.1l1.3 .4-1.3 .5M254.3 93.2h.7M363.4 87.6a.64 .64 0 0 1 .7 .7 .64 .64 0 0 1-.7 .6zM379.1 92.6v.7h.6l-.1-.1 .1-.6h.5l.1 .2-.1 .5M379.5 87.6l-.4 .9h.8M379.8 88v.9M388 97.7v.6l.6 .1-.2-.2 .2-.5h.5l.1 .2-.1 .5M338.4 119.4a.64 .64 0 0 1 .7 .7 .64 .64 0 0 1-.7 .6zM340.4 119.4v1.3l-.8-1.3v1.3M359.5 119.4a.64 .64 0 0 1 .7 .7 .64 .64 0 0 1-.7 .6zM379.5 107h.8M379.9 106.9v.8l-.9-.3"/>
<path d="M388.4 112.1h.8M388.8 111.9v.8l-.9-.3M137.9 134.4l-.5-.1-.2 .1 .1 .4 .5 .3 .1 .2-.3 .2h-.4M137.9 121.7l-.5-.1-.2 .1 .1 .4 .5 .3 .1 .2-.3 .2h-.4M152.6 134.9l.5-.1 .1-.4-.6-.1v1.2h.5l.1-.1 .1-.3-.3-.2M152.6 122.2l.5-.1 .1-.4-.6-.1v1.2h.5l.1-.1 .1-.3-.3-.2M347.7 136.4h.6M357.9 120.2h1M379.1 120.6v.6l.6 .1-.1-.2 .1-.5h.5l.1 .2-.1 .5M379.5 135h.8M379.9 134.8v.8l-.9-.3M137.9 147.1l-.5-.1-.2 .1 .1 .4 .5 .3 .1 .2-.3 .2h-.4"/>
<path d="M137.9 159.8l-.5-.1-.2 .1 .1 .4 .5 .3 .1 .2-.3 .2h-.4M152.6 147.6l.5-.1 .1-.4-.6-.1v1.2h.5l.1-.1 .1-.3-.3-.2M152.6 160.3l.5-.1 .1-.4-.6-.1v1.2h.5l.1-.1 .1-.3-.3-.2M354.2 173.3a.64 .64 0 0 1 .7 .7 .64 .64 0 0 1-.7 .6zM354.2 160.6a.64 .64 0 0 1 .7 .7 .64 .64 0 0 1-.7 .6zM369.7 160.8l.1-.2a.69 .69 0 0 1 .5 .7 .69 .69 0 0 1-.5 .6l-.2-.2-.1-.3zM370.6 173.3h-.6l-.1 .7 .5-.2 .2 .3v.3l-.2 .2-.5-.1M354.2 186a.64 .64 0 0 1 .7 .7 .64 .64 0 0 1-.7 .6zM354.2 198.7a.64 .64 0 0 1 .7 .7 .64 .64 0 0 1-.7 .6zM369.7 186.2l.1-.2a.69 .69 0 0 1 .5 .7 .69 .69 0 0 1-.5 .6l-.2-.2-.1-.3zM369.7 198.8l.1-.1a.69 .69 0 0 1 .5 .7 .69 .69 0 0 1-.5 .6 .83 .83 0 0 1-.1-1.2zM128.2 222.8a.64 .64 0 0 1 .7 .7 .64 .64 0 0 1-.7 .6z"/>
<path d="M128.9 220.3a.64 .64 0 0 1 .7 .6 .64 .64 0 0 1-.7 .7zM287.5 272.3v1.1l.2 .2M292.6 261.7l.6-.1v-.2l-.4-.1-.2 .2 .1 .6h.5"/>
</g>
<g fill="none" stroke="#840000" stroke-width=".25">
<path d="M26.9 31.8h2.1v5.1h-2.1zM39.6 31.8h2.1v5.1h-2.1zM44.4 38.4h5.1v2h-5.1zM44.4 28.2h5.1v2.1h-5.1zM76.2 28h20.3v27.9h-20.3zM99.3 25.4h2v5.1h-2zM103.1 25.4h2.1v5.1h-2.1zM106.9 25.4h2.1v5.1h-2.1zM110.7 25.4h2.1v5.1h-2.1zM129.8 25.4h2v5.1h-2zM137.4 25.4h2v5.1h-2zM196.8 28h2.6v7.6h-2.6z"/>
<path d="M208.3 33.3h5.1v2h-5.1zM214.9 36.9h2v5h-2zM223.5 31.8l10.2 5.1-10.2 5zM240 35.9h5.1v2h-5.1zM269.5 29.2h2v5.1h-2zM284.5 25.4l7.6 3.8-7.6 3.9zM371.1 31.8h2v5.1h-2zM382.5 31.8h2.1v5.1h-2.1zM196.8 43.2h2.6v7.6h-2.6zM208.3 48.6h5.1v2h-5.1zM214.9 52.1h2v5.1h-2zM223.5 47l10.2 5.1-10.2 5.1z"/>
<path d="M240 51.1h5.1v2h-5.1zM284.5 52.1l7.6 3.8-7.6 3.8zM370.8 43.2h2.6l-1.3 2.6zM370.8 45.8h2.6M382.3 43.2h2.5l-1.3 2.6zM382.3 45.8h2.5M40.9 66.1h2v5.1h-2zM44.4 72.7h5.1v2h-5.1zM44.4 62.5h5.1v2.1h-5.1zM222.5 73.7h2v5.1h-2zM284.5 78.8l7.6 3.8-7.6 3.8zM40.9 95.3h2v5.1h-2z"/>
<path d="M44.4 91.7h5.1v2.1h-5.1zM368.3 90.2h2.5v5.1h-2.5zM44.4 101.9h5.1v2h-5.1zM284.5 105.4l7.6 3.9-7.6 3.8zM52.3 139.7h2.1v5.1h-2.1zM91.7 128.3h2v5.1h-2zM95.5 128.3h2v5.1h-2zM100.6 128.3h2v5.1h-2zM104.4 128.3h2v5.1h-2zM109.5 128.3h2v5.1h-2zM113.3 128.3h2v5.1h-2zM118.4 128.3h2v5.1h-2z"/>
<path d="M122.2 128.3h2v5.1h-2zM146 137.2h2.6v10.2h-2.6zM146 124.5h2.6v10.2h-2.6zM285.7 135.9h10.2v15.3h-10.2zM146 149.9h2.6v10.2h-2.6zM350.5 155h2.6v10.1h-2.6zM146 162.6h2.6v10.2h-2.6zM275.8 179.1h2.1v5.1h-2.1zM289.8 179.1h2v5.1h-2zM303.8 179.1h2v5.1h-2zM350.5 167.7h2.6v10.1h-2.6zM350.5 180.4h2.6v10.1h-2.6z"/>
<path d="M350.5 193.1h2.6v10.1h-2.6zM109.5 215.9h2v5.1h-2zM115.6 218.5h20.3v15.2h-20.3zM148.8 215.9h2.1v5.1h-2.1zM155.2 215.9h2v5.1h-2z"/>
</g>
<g fill="none" stroke="#840000" stroke-width=".51">
<path d="M50 35.1h4.1M50 33.6h4.1M245.6 57.9h4.1M245.6 56.4h4.1M245.6 42.7h4.1M245.6 41.2h4.1M50 69.4h4.1M50 67.9h4.1M50 98.6h4.1M50 97.1h4.1M81.8 84.6h4.1M81.8 83.1h4.1"/>
<path d="M221.5 90.7h4.1M221.5 92.2h4.1M227.8 90.7h4.1M227.8 92.2h4.1M381.5 98.6h4.1M381.5 97.1h4.1M390.4 98.6h4.1M390.4 97.1h4.1M381.5 129.1h4.1M381.5 127.5h4.1M51.3 153.2h4.1M51.3 151.7h4.1"/>
<path d="M61.5 157h4M61.5 155.5h4M278.6 144.3h4.1M278.6 142.8h4.1M163.1 219.2h4M163.1 217.7h4"/>
<circle cx="265.4" cy="271.8" r="1.27"/>
<circle cx="271.8" cy="271.8" r="1.27"/>
<circle cx="278.1" cy="271.8" r="1.27"/>
</g>
<g fill="#ffffc2" stroke="#ffffc2" stroke-width=".18">
<path d="M284.5 105.4l7.6 3.9-7.6 3.8z"/>
<path d="M284.5 78.8l7.6 3.8-7.6 3.8z"/>
<path d="M284.5 52.1l7.6 3.8-7.6 3.8z"/>
<path d="M284.5 25.4l7.6 3.8-7.6 3.9z"/>
<path d="M285.7 135.9h10.2v15.3h-10.2z"/>
<path d="M76.2 28h20.3v27.9h-20.3z"/>
<path d="M146 137.2h2.6v10.2h-2.6z"/>
<path d="M115.6 218.5h20.3v15.2h-20.3z"/>
<path d="M350.5 167.7h2.6v10.1h-2.6z"/>
<path d="M350.5 155h2.6v10.1h-2.6z"/>
<path d="M368.3 90.2h2.5v5.1h-2.5z"/>
<path d="M146 149.9h2.6v10.2h-2.6z"/>
<path d="M146 124.5h2.6v10.2h-2.6z"/>
<path d="M146 162.6h2.6v10.2h-2.6z"/>
<path d="M350.5 180.4h2.6v10.1h-2.6z"/>
<path d="M350.5 193.1h2.6v10.1h-2.6z"/>
<path d="M73.7 134.7h15.2v24.1h-15.2z"/>
<path d="M223.5 31.8l10.2 5.1-10.2 5z"/>
<path d="M223.5 47l10.2 5.1-10.2 5.1z"/>
<path d="M342.9 24.2h7.6v86.3h-7.6z"/>
<path d="M350.5 24.2h5.1v86.3h-5.1z"/>
<path d="M196.8 28h2.6v7.6h-2.6z"/>
<path d="M196.8 43.2h2.6v7.6h-2.6z"/>
<circle cx="278.1" cy="271.8" r="1.27"/>
<circle cx="271.8" cy="271.8" r="1.27"/>
<circle cx="265.4" cy="271.8" r="1.27"/>
</g>
<g fill="none" stroke="#840000" stroke-width="1.3">
<circle cx="265.4" cy="260.4" r="1.27"/>
<circle cx="271.8" cy="260.4" r="1.27"/>
<circle cx="278.1" cy="260.4" r="1.27"/>
</g>
<path d="M396.1 257.6l.6-.5 .9 .6a.62 .62 0 0 0 1 0l.4-.2 .3-1.4h1.5l.1 .5a1.13 1.13 0 0 0 .7 1.2l.5 .2 1.3-.9 1.1 1.1-.4 .7a.75 .75 0 0 0-.2 1.2l.2 .4 1.5 .3v1.5l-1.4 .3-.1 .1a1.18 1.18 0 0 0-.2 1.4l.6 .8-.1 .2-1 .9-.8-.5a.54 .54 0 0 0-.9 0l-1-2.4a2.33 2.33 0 0 0 .8-1.9 1.54 1.54 0 0 0-2.5-.7 1.54 1.54 0 0 0 .5 2.6l-1.1 2.4a.69 .69 0 0 0-1.1 .1l-.6 .4-1.1-1.1 .8-1.2-.2-.5a.71 .71 0 0 0-1-.7l-.7-.2v-1.5l.5-.1a1.11 1.11 0 0 0 1.2-.7 .72 .72 0 0 0-.2-1.2l-.4-.6z" fill="#840000" stroke="#840000" stroke-width=".18"/>
<g fill="none" stroke="#008400" stroke-width=".18">
<path d="M27.9 38.1v1.3h15.3M40.6 24.2v6.3M40.6 38.1v6.4M43.2 29.2h-15.3v1.3M50.8 29.2h8.9v3.9h14M52.1 29.2v1.3M52.1 38.1v1.3M73.7 35.6h-14v3.8h-8.9M83.8 24.2v1.2M88.9 24.2v1.2M99.1 33.1h13.9M99.1 38.1h13.9"/>
<path d="M99.1 35.6h13.9M100.3 22.9v1.3M100.3 31.8v1.3M104.1 22.9v1.3M104.1 31.8v3.8M107.9 22.9v1.3M107.9 31.8v6.3M111.8 22.9v1.3M111.8 31.8v8.9M130.8 22.9v1.3M130.8 31.8v14M138.4 22.9v1.3"/>
<path d="M138.4 31.8v16.5M203.2 29.2h1.3M203.2 31.8h1.3M203.2 34.3h3.8M214.6 34.3h6.4M215.9 34.3v1.3M236.2 36.9h2.6M237.5 36.9v6.3h-17.8v-3.8M246.4 36.9h3.8M247.6 36.9v1.2M270.5 35.6v1.3h17.8v-1.3M270.5 25.4v2.6"/>
<path d="M274.3 36.9v53.3h14v-1.3M278.1 29.2h2.6M295.9 29.2h3.8M337.8 29.2h2.6M337.8 39.4h2.6M337.8 31.8h2.6M337.8 36.9h2.6M372.1 28v2.5M372.1 38.1v2.6M383.5 28v2.5M383.5 38.1v2.6M73.7 43.2h-10.2v30.5h-12.7"/>
<path d="M73.7 48.3h-7.7v44.4h-15.2M73.7 40.7h-11.5v22.8h-11.4M73.7 50.8h-6.4v52.1h-16.5M83.8 58.5v1.2M88.9 58.5v1.2M99.1 40.7h13.9M99.1 50.8h1.2v8.9M99.1 48.3h43.1M99.1 45.8h43.1M203.2 47h1.3M203.2 44.5h1.3M203.2 49.6h3.8"/>
<path d="M215.9 43.2v1.3M215.9 58.5v1.2M221 49.6h-5.1v1.2M236.2 52.1h2.6M237.5 52.1v6.4h-17.8v-3.9M247.6 45.8v1.2M247.6 52.1v1.3M278.1 55.9h2.6M295.9 55.9h3.8M336.5 47h3.9M336.5 44.5h3.9M372.1 48.3v2.5"/>
<path d="M383.5 48.3v2.5M41.9 63.5h1.3M41.9 61v3.8M41.9 72.4v6.4M41.9 73.7h1.3M52.1 63.5v1.3M52.1 72.4v1.3M83.8 78.8v1.2M223.5 71.2v1.2M247.6 61v1.3M288.3 62.3v1.2h-17.8M336.5 72.4h3.9"/>
<path d="M336.5 75h3.9M41.9 92.7h1.3M41.9 90.2v3.8M52.1 92.7v1.3M83.8 87.7v1.2M223.5 82.6h12.7v1.3M223.5 80v7.7M223.5 95.3v6.3M229.9 82.6v5.1M229.9 95.3v6.3M236.2 99.1v2.5M278.1 82.6h2.6"/>
<path d="M295.9 82.6h3.8M336.5 95.3h3.9M336.5 90.2h3.9M336.5 87.7h3.9M336.5 85.1h3.9M336.5 92.7h3.9M336.5 80h3.9M374.6 91.5h17.8v2.5M374.6 94h1.3v10.2M383.5 90.2v3.8M41.9 101.6v5.1M41.9 102.9h1.3"/>
<path d="M52.1 101.6v1.3M279.4 109.3h1.3M288.3 115.6v1.3h-8.9M383.5 101.6v2.6M392.4 101.6v2.6M53.3 137.2v1.3M66 138.5h5.1M66 135.9h5.1M81.3 125.8h41.9v1.2M81.3 124.5v7.6M92.7 125.8v1.2M92.7 134.7v1.2"/>
<path d="M96.5 125.8v1.2M96.5 134.7v3.8M101.6 125.8v1.2M101.6 134.7v7.6M105.4 125.8v1.2M105.4 134.7v10.1M110.5 125.8v1.2M110.5 134.7v13.9M114.3 125.8v1.2M114.3 134.7v16.5M119.4 125.8v1.2M119.4 134.7v20.3"/>
<path d="M123.2 134.7v22.8M141 130.8h1.2M141 133.4h1.2M142.2 125.8h-13.9v10.1h-36.9M142.2 128.3h-12.7v10.2h-38.1M142.2 138.5h-10.1v3.8h-40.7M280.7 128.3v11.4M290.8 128.3v2.5M339.1 138.5h3.8M339.1 135.9h3.8M339.1 128.3h3.8M339.1 133.4h3.8"/>
<path d="M355.6 125.8h3.8M355.6 138.5h3.8M355.6 135.9h3.8M355.6 128.3h3.8M355.6 133.4h3.8M383.5 122v2.5M383.5 132.1v2.6M49.5 147.4h21.6M53.3 156.2v6.4h28M53.3 146.1v2.5M63.5 151.2v1.2M69.8 155h1.3"/>
<path d="M71.1 152.4h-1.3v10.2M91.4 157.5h36.9v8.9h13.9M91.4 155h38.1v8.9h12.7M91.4 151.2h40.7v2.5h10.1M91.4 148.6h41.9v2.6h8.9M141 156.2h1.2M141 158.8h1.2M141 143.5h1.2M141 146.1h1.2M142.2 141h-8.9v3.8h-41.9M280.7 147.4v10.1M290.8 156.2v1.3"/>
<path d="M339.1 141h3.8M344.2 158.8h2.5M345.4 156.2h1.3M63.5 160.1v2.5M81.3 161.3v2.6M141 168.9h1.2M141 171.5h1.2M276.9 176.6v1.2M290.8 176.6v1.2M304.8 176.6v1.2M344.2 161.3h2.5M344.2 163.9h2.5"/>
<path d="M344.2 171.5h2.5M344.2 174h2.5M344.2 176.6h2.5M345.4 168.9h1.3M276.9 185.5v1.2h3.8M290.8 185.5v1.2h3.8M304.8 185.5v1.2h3.8M344.2 184.2h2.5M344.2 186.7h2.5M344.2 189.3h2.5M344.2 196.9h2.5M344.2 199.4h2.5"/>
<path d="M345.4 181.6h1.3M345.4 194.3h1.3M110.5 212.1v2.6M110.5 213.4h54.6v1.3M125.7 213.4v2.5M149.9 213.4v1.3M156.2 213.4v1.3M285.7 218.5h12.7M285.7 205.8h12.7M344.2 202h2.5M104.1 228.6h8.9M104.1 223.6h8.9"/>
<path d="M110.5 222.3v1.3M125.7 236.3v2.5M138.4 223.6h5.1M138.4 221h5.1M149.9 222.3v6.3h-11.5M156.2 222.3v8.9h-17.8M165.1 222.3v15.2h-39.4M285.7 231.2h12.7M285.7 243.9h12.7"/>
</g>
<g fill="none" stroke="#0000c2" stroke-width=".18">
<path d="M376.5 20.7l.6-.1v-.4l-.6-.2v1.3M377.6 20l.3 1.3 .3-.9 .2 .9 .3-1.3M379.2 20.7l.6-.1 .1-.4-.7-.2v1.3M379.5 20.7l.4 .6M380.4 20.4l.4-.4v1.3M380.4 21.3h.7M382.6 20.5h.4l.2 .2-.1 .5h-.5M382.6 20.5v1.2M383.8 20v.2M383.8 20.5v.8M384.4 20.6l.2-.1h.3v.8M384.4 20.5v.8"/>
<path d="M386.4 20.2l.5-.2 .3 .4-.1 .2-.7 .7h.8"/>
</g>
<g fill="#008400" stroke="#008400" stroke-width=".25">
<circle cx="110.5" cy="223.6" r=".51"/>
<circle cx="236.2" cy="82.6" r=".51"/>
<circle cx="41.9" cy="63.5" r=".51"/>
<circle cx="274.3" cy="36.9" r=".51"/>
<circle cx="69.9" cy="155" r=".51"/>
<circle cx="81.3" cy="162.6" r=".51"/>
<circle cx="52.1" cy="102.9" r=".51"/>
<circle cx="52.1" cy="92.7" r=".51"/>
<circle cx="52.1" cy="73.7" r=".51"/>
<circle cx="52.1" cy="63.5" r=".51"/>
<circle cx="41.9" cy="92.7" r=".51"/>
<circle cx="41.9" cy="102.9" r=".51"/>
<circle cx="41.9" cy="73.7" r=".51"/>
<circle cx="138.4" cy="48.3" r=".51"/>
<circle cx="130.8" cy="45.8" r=".51"/>
<circle cx="223.5" cy="82.6" r=".51"/>
<circle cx="40.6" cy="39.4" r=".51"/>
<circle cx="274.3" cy="63.5" r=".51"/>
<circle cx="111.8" cy="40.7" r=".51"/>
<circle cx="107.9" cy="38.1" r=".51"/>
<circle cx="104.1" cy="35.6" r=".51"/>
<circle cx="100.3" cy="33.1" r=".51"/>
<circle cx="247.6" cy="36.9" r=".51"/>
<circle cx="237.5" cy="52.1" r=".51"/>
<circle cx="237.5" cy="36.9" r=".51"/>
<circle cx="215.9" cy="34.3" r=".51"/>
<circle cx="229.9" cy="82.6" r=".51"/>
<circle cx="383.5" cy="91.5" r=".51"/>
<circle cx="92.7" cy="125.8" r=".51"/>
<circle cx="40.6" cy="29.2" r=".51"/>
<circle cx="52.1" cy="39.4" r=".51"/>
<circle cx="52.1" cy="29.2" r=".51"/>
<circle cx="125.7" cy="237.5" r=".51"/>
<circle cx="156.2" cy="213.4" r=".51"/>
<circle cx="149.9" cy="213.4" r=".51"/>
<circle cx="110.5" cy="213.4" r=".51"/>
<circle cx="123.2" cy="157.5" r=".51"/>
<circle cx="119.4" cy="155" r=".51"/>
<circle cx="114.3" cy="151.2" r=".51"/>
<circle cx="110.5" cy="148.6" r=".51"/>
<circle cx="105.4" cy="144.8" r=".51"/>
<circle cx="96.5" cy="138.5" r=".51"/>
<circle cx="101.6" cy="142.3" r=".51"/>
<circle cx="81.3" cy="125.8" r=".51"/>
<circle cx="96.5" cy="125.8" r=".51"/>
<circle cx="101.6" cy="125.8" r=".51"/>
<circle cx="105.4" cy="125.8" r=".51"/>
<circle cx="110.5" cy="125.8" r=".51"/>
<circle cx="114.3" cy="125.8" r=".51"/>
<circle cx="119.4" cy="125.8" r=".51"/>
<circle cx="53.3" cy="147.4" r=".51"/>
<circle cx="69.9" cy="162.6" r=".51"/>
<circle cx="63.5" cy="162.6" r=".51"/>
<circle cx="92.7" cy="135.9" r=".51"/>
</g>
<use href="#words"/>
</svg>
